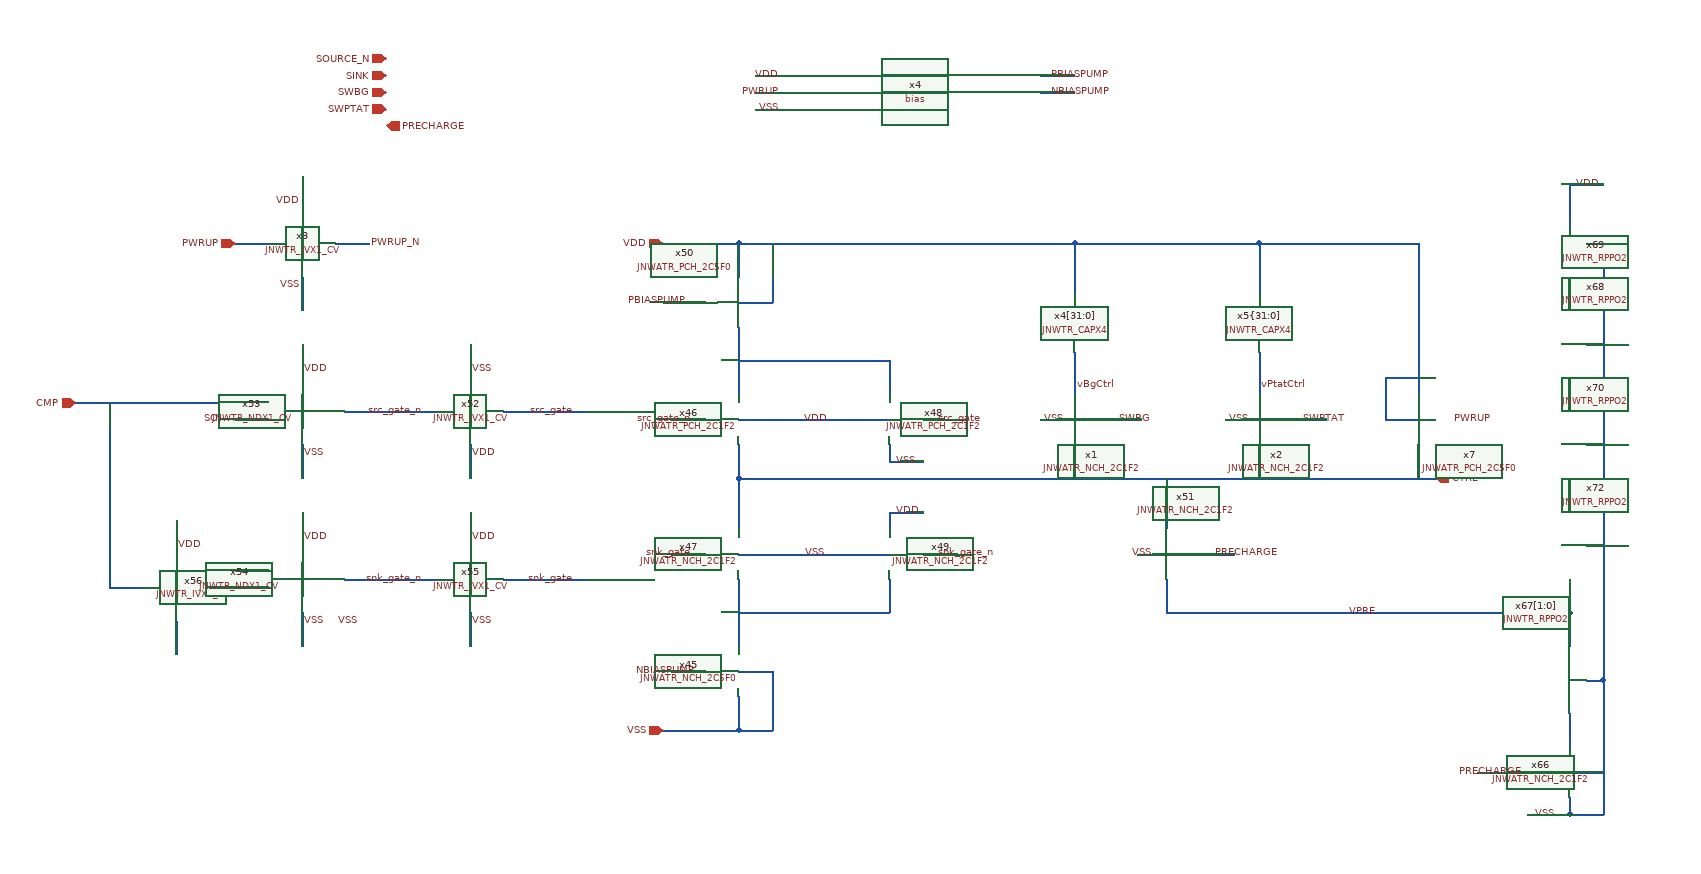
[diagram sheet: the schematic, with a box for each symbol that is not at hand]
v {xschem version=3.4.6 file_version=1.2}
G {}
K {}
V {}
S {}
E {}
N 1890 -520 1970 -520 {
lab=VPRE}
N 1970 -300 1970 -280 {
lab=VSS}
N 1860 -330 1930 -330 {
lab=PRECHARGE}
N 1920 -280 1970 -280 {
lab=VSS}
N 1970 -280 2010 -280 {
lab=VSS}
N 1970 -920 1970 -880 {
lab=#net1}
N 1970 -1030 1970 -980 {
lab=VDD}
N 1970 -1030 2010 -1030 {
lab=VDD}
N 1970 -800 1970 -760 {
lab=#net2}
N 2010 -440 2010 -280 {
lab=VSS}
N 1970 -560 1970 -520 {lab=VPRE}
N 2010 -960 2010 -440 {
lab=VSS}
N 980 -420 980 -380 {
lab=VSS}
N 890 -890 940 -890 {
lab=PBIASPUMP}
N 900 -450 940 -450 {
lab=NBIASPUMP}
N 1160 -720 1160 -700 {
lab=VSS}
N 1160 -700 1200 -700 {
lab=VSS}
N 1200 -750 1225 -750 {
lab=src_gate}
N 1160 -640 1160 -620 {
lab=VDD}
N 1160 -640 1200 -640 {
lab=VDD}
N 1200 -590 1240 -590 {
lab=snk_gate_n}
N 890 -380 980 -380 {
lab=VSS}
N 980 -560 980 -480 {
lab=#net3}
N 1160 -560 1160 -520 {
lab=#net3}
N 980 -520 1160 -520 {
lab=#net3}
N 1530 -590 1570 -590 {
lab=PRECHARGE}
N 1455 -590 1490 -590 {
lab=VSS}
N 1490 -680 1490 -620 {
lab=CTRL}
N 380 -750 420 -750 {lab=SOURCE_N}
N 980 -720 980 -680 {
lab=CTRL}
N 980 -680 980 -620 {lab=CTRL}
N 980 -960 1380 -960 {lab=VDD}
N 890 -960 980 -960 {lab=VDD}
N 510 -760 620 -760 {lab=src_gate_n}
N 700 -760 800 -760 {lab=src_gate}
N 190 -770 420 -770 {lab=CMP}
N 230 -770 230 -550 {lab=CMP}
N 380 -570 420 -570 {lab=SINK}
N 980 -590 1160 -590 {lab=VSS}
N 900 -750 940 -750 {lab=src_gate_n}
N 980 -750 1160 -750 {lab=VDD}
N 230 -550 270 -550 {lab=CMP}
N 350 -550 420 -550 {lab=#net4}
N 510 -560 620 -560 {lab=snk_gate_n}
N 1490 -560 1490 -520 {lab=VPRE}
N 1380 -830 1380 -780 {lab=vBgCtrl}
N 1380 -960 1600 -960 {lab=VDD}
N 1640 -750 1680 -750 {lab=SWPTAT}
N 1420 -750 1460 -750 {lab=SWBG}
N 380 -960 420 -960 {lab=PWRUP}
N 500 -960 540 -960 {lab=PWRUP_N}
N 1790 -720 1790 -680 {lab=CTRL}
N 1790 -960 1790 -780 {lab=VDD}
N 460 -520 460 -480 {lab=VSS}
N 460 -640 460 -600 {lab=VDD}
N 310 -630 310 -590 {lab=VDD}
N 310 -510 310 -470 {lab=#net8}
N 700 -560 800 -560 {lab=snk_gate}
N 980 -450 1020 -450 {lab=VSS}
N 1020 -450 1020 -380 {lab=VSS}
N 980 -380 1020 -380 {lab=VSS}
N 660 -520 660 -480 {lab=VSS}
N 660 -640 660 -600 {lab=VDD}
N 460 -720 460 -680 {lab=VSS}
N 460 -840 460 -800 {lab=VDD}
N 660 -840 660 -800 {lab=VSS}
N 660 -720 660 -680 {lab=VDD}
N 460 -920 460 -880 {lab=VSS}
N 460 -1040 460 -1000 {lab=VDD}
N 1750 -750 1790 -750 {lab=VDD}
N 1750 -800 1750 -750 {lab=VDD}
N 1750 -800 1790 -800 {lab=VDD}
N 900 -590 940 -590 {lab=snk_gate}
N 980 -960 980 -920 {lab=VDD}
N 980 -890 1020 -890 {lab=VDD}
N 1340 -750 1380 -750 {lab=VSS}
N 1560 -750 1600 -750 {lab=VSS}
N 980 -680 1810 -680 {lab=CTRL}
N 1380 -720 1380 -680 {lab=CTRL}
N 1600 -720 1600 -680 {lab=CTRL}
N 1600 -830 1600 -780 {lab=vPtatCtrl}
N 1160 -820 1160 -780 {lab=#net9}
N 980 -820 1160 -820 {lab=#net9}
N 980 -860 980 -780 {lab=#net9}
N 1020 -960 1020 -890 {lab=VDD}
N 1380 -960 1380 -900 {lab=VDD}
N 1600 -960 1600 -900 {lab=VDD}
N 1600 -960 1790 -960 {lab=VDD}
N 1490 -520 1890 -520 {lab=VPRE}
N 1990 -840 2010 -840 {lab=VSS}
N 1990 -960 2010 -960 {lab=VSS}
N 1990 -720 2010 -720 {lab=VSS}
N 1990 -600 2010 -600 {lab=VSS}
N 1990 -440 2010 -440 {lab=VSS}
N 1970 -330 1990 -330 {lab=VSS}
N 1990 -330 2010 -330 {lab=VSS}
N 1970 -520 1970 -480 {lab=VPRE}
N 1970 -400 1970 -360 {lab=#net10}
N 1970 -680 1970 -640 {lab=#net11}
N 1000 -1160 1040 -1160 {lab=VDD}
N 1000 -1140 1040 -1140 {lab=PWRUP}
N 1000 -1120 1040 -1120 {lab=VSS}
N 1340 -1160 1380 -1160 {lab=PBIASPUMP}
N 1340 -1140 1380 -1140 {lab=NBIASPUMP}
C {devices/lab_wire.sym} 1975 -1030 0 1 {name=p117 sig_type=std_logic lab=VDD}
C {devices/lab_wire.sym} 1955 -280 0 0 {name=p119 sig_type=std_logic lab=VSS}
C {JNW_ATR_SKY130A/JNWATR_NCH_2C1F2.sym} 1930 -330 0 0 {name=x66 }
C {devices/lab_wire.sym} 1915 -330 0 0 {name=p125 sig_type=std_logic lab=PRECHARGE}
C {JNW_TR_SKY130A/JNWTR_RPPO2.sym} 1970 -480 3 1 {name=x67[1:0]}
C {JNW_TR_SKY130A/JNWTR_RPPO2.sym} 1970 -880 3 1 {name=x68 }
C {JNW_TR_SKY130A/JNWTR_RPPO2.sym} 1970 -1000 3 1 {name=x69 }
C {JNW_TR_SKY130A/JNWTR_RPPO2.sym} 1970 -760 3 1 {name=x70 }
C {JNW_TR_SKY130A/JNWTR_RPPO2.sym} 1970 -640 3 1 {name=x72 }
C {devices/ipin.sym} 560 -1160 0 0 {name=p128 lab=SINK
}
C {devices/ipin.sym} 560 -1180 0 0 {name=p129 lab=SOURCE_N}
C {devices/ipin.sym} 890 -960 0 0 {name=p94 lab=VDD}
C {devices/opin.sym} 1810 -680 0 0 {name=p95 lab=CTRL}
C {devices/ipin.sym} 890 -380 0 0 {name=p96 lab=VSS
}
C {devices/ipin.sym} 560 -1100 2 1 {name=p97 lab=PRECHARGE
}
C {JNW_ATR_SKY130A/JNWATR_NCH_2C5F0.sym} 940 -450 0 0 {name=x45 }
C {devices/lab_wire.sym} 1055 -750 0 1 {name=p98 sig_type=std_logic lab=VDD}
C {JNW_ATR_SKY130A/JNWATR_PCH_2C1F2.sym} 940 -750 0 0 {name=x46 }
C {JNW_ATR_SKY130A/JNWATR_NCH_2C1F2.sym} 940 -590 0 0 {name=x47 }
C {JNW_ATR_SKY130A/JNWATR_PCH_2C1F2.sym} 1200 -750 0 1 {name=x48 }
C {devices/lab_wire.sym} 1165 -700 0 1 {name=p99 sig_type=std_logic lab=VSS}
C {JNW_ATR_SKY130A/JNWATR_NCH_2C1F2.sym} 1200 -590 0 1 {name=x49 }
C {devices/lab_wire.sym} 1085 -590 2 1 {name=p100 sig_type=std_logic lab=VSS}
C {devices/lab_wire.sym} 1215 -590 0 1 {name=p101 sig_type=std_logic lab=snk_gate_n}
C {JNW_ATR_SKY130A/JNWATR_PCH_2C5F0.sym} 940 -890 0 0 {name=x50 }
C {devices/lab_wire.sym} 1165 -640 0 1 {name=p102 sig_type=std_logic lab=VDD}
C {JNW_ATR_SKY130A/JNWATR_NCH_2C1F2.sym} 1530 -590 0 1 {name=x51 }
C {devices/lab_wire.sym} 1475 -590 0 0 {name=p103 sig_type=std_logic lab=VSS}
C {devices/lab_wire.sym} 920 -890 0 0 {name=p107 sig_type=std_logic lab=PBIASPUMP}
C {devices/lab_wire.sym} 930 -450 0 0 {name=p108 sig_type=std_logic lab=NBIASPUMP}
C {devices/lab_wire.sym} 605 -760 2 1 {name=p110 sig_type=std_logic lab=src_gate_n}
C {devices/lab_wire.sym} 785 -560 0 0 {name=p111 sig_type=std_logic lab=snk_gate}
C {devices/ipin.sym} 190 -770 0 0 {name=p112 lab=CMP}
C {devices/lab_wire.sym} 785 -760 2 1 {name=p122 sig_type=std_logic lab=src_gate}
C {JNW_TR_SKY130A/JNWTR_IVX1_CV.sym} 620 -760 2 1 {name=x52 }
C {devices/lab_wire.sym} 410 -750 2 1 {name=p156 sig_type=std_logic lab=SOURCE_N

}
C {devices/lab_wire.sym} 1215 -750 0 1 {name=p167 sig_type=std_logic lab=src_gate}
C {devices/lab_wire.sym} 605 -560 0 0 {name=p168 sig_type=std_logic lab=snk_gate_n}
C {devices/lab_wire.sym} 660 -710 2 0 {name=p169 sig_type=std_logic lab=VDD

}
C {devices/lab_wire.sym} 660 -810 0 1 {name=p170 sig_type=std_logic lab=VSS

}
C {devices/lab_wire.sym} 460 -810 0 1 {name=p104 sig_type=std_logic lab=VDD

}
C {JNW_TR_SKY130A/JNWTR_NDX1_CV.sym} 420 -750 0 0 {name=x53 }
C {devices/lab_wire.sym} 460 -710 2 0 {name=p105 sig_type=std_logic lab=VSS

}
C {devices/lab_wire.sym} 460 -610 0 1 {name=p132 sig_type=std_logic lab=VDD

}
C {devices/lab_wire.sym} 460 -510 2 0 {name=p133 sig_type=std_logic lab=VSS

}
C {devices/lab_wire.sym} 410 -570 0 0 {name=p157 sig_type=std_logic lab=SINK

}
C {JNW_TR_SKY130A/JNWTR_IVX1_CV.sym} 620 -560 0 0 {name=x55 }
C {devices/lab_wire.sym} 660 -610 0 1 {name=p158 sig_type=std_logic lab=VDD

}
C {devices/lab_wire.sym} 660 -510 2 0 {name=p159 sig_type=std_logic lab=VSS

}
C {JNW_TR_SKY130A/JNWTR_IVX1_CV.sym} 270 -550 0 0 {name=x56 }
C {devices/lab_wire.sym} 310 -600 0 1 {name=p160 sig_type=std_logic lab=VDD

}
C {devices/lab_wire.sym} 500 -510 2 0 {name=p161 sig_type=std_logic lab=VSS

}
C {JNW_TR_SKY130A/JNWTR_NDX1_CV.sym} 420 -550 0 0 {name=x54 }
C {devices/lab_wire.sym} 1430 -750 0 1 {name=p171 sig_type=std_logic lab=SWBG

}
C {devices/lab_wire.sym} 1650 -750 0 1 {name=p183 sig_type=std_logic lab=SWPTAT

}
C {devices/lab_wire.sym} 1600 -790 0 1 {name=p184 sig_type=std_logic lab=vPtatCtrl

}
C {devices/lab_wire.sym} 1380 -790 0 1 {name=p185 sig_type=std_logic lab=vBgCtrl

}
C {devices/ipin.sym} 560 -1120 0 0 {name=p1 lab=SWPTAT
}
C {devices/ipin.sym} 560 -1140 0 0 {name=p2 lab=SWBG}
C {devices/lab_wire.sym} 1370 -750 2 1 {name=p4 sig_type=std_logic lab=VSS

}
C {JNW_ATR_SKY130A/JNWATR_NCH_2C1F2.sym} 1420 -750 0 1 {name=x1 }
C {devices/lab_wire.sym} 1590 -750 2 1 {name=p7 sig_type=std_logic lab=VSS

}
C {JNW_ATR_SKY130A/JNWATR_NCH_2C1F2.sym} 1640 -750 0 1 {name=x2 }
C {devices/ipin.sym} 380 -960 0 0 {name=p3 lab=PWRUP
}
C {JNW_TR_SKY130A/JNWTR_IVX1_CV.sym} 420 -960 0 0 {name=x3 }
C {devices/lab_wire.sym} 460 -910 2 1 {name=p10 sig_type=std_logic lab=VSS}
C {devices/lab_wire.sym} 460 -1010 0 0 {name=p11 sig_type=std_logic lab=VDD}
C {JNW_ATR_SKY130A/JNWATR_PCH_2C5F0.sym} 1830 -750 0 1 {name=x7 }
C {devices/lab_wire.sym} 1830 -750 0 1 {name=p13 sig_type=std_logic lab=PWRUP}
C {devices/lab_pin.sym} 540 -960 0 1 {name=p5 sig_type=std_logic lab=PWRUP_N}
C {devices/lab_wire.sym} 925 -750 2 1 {name=p6 sig_type=std_logic lab=src_gate_n}
C {devices/lab_wire.sym} 925 -590 0 0 {name=p8 sig_type=std_logic lab=snk_gate}
C {JNW_TR_SKY130A/JNWTR_CAPX4.sym} 1380 -840 0 0 {name=x4[31:0]}
C {JNW_TR_SKY130A/JNWTR_CAPX4.sym} 1600 -840 0 0 {name=x5\{31:0]}
C {devices/lab_wire.sym} 1705 -520 0 1 {name=p9 sig_type=std_logic lab=VPRE}
C {devices/lab_wire.sym} 1545 -590 0 1 {name=p12 sig_type=std_logic lab=PRECHARGE}
C {LELO_TORD_SKY130A/bias.sym} 1190 -1140 0 0 {name=x4}
C {devices/lab_wire.sym} 1030 -1160 0 0 {name=p14 sig_type=std_logic lab=VDD}
C {devices/lab_wire.sym} 1030 -1120 0 0 {name=p15 sig_type=std_logic lab=VSS}
C {devices/lab_wire.sym} 1030 -1140 0 0 {name=p16 sig_type=std_logic lab=PWRUP}
C {devices/lab_wire.sym} 1350 -1140 0 1 {name=p17 sig_type=std_logic lab=NBIASPUMP}
C {devices/lab_wire.sym} 1350 -1160 0 1 {name=p18 sig_type=std_logic lab=PBIASPUMP}
